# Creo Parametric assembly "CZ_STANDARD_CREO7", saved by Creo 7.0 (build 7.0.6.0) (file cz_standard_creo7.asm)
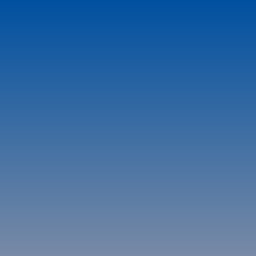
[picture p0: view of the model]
Units: Custom; MM, KILOGRAM, SECS

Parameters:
  BEARBEITER = "."
  ERSTELLUNGSDATUM = "."
  KONSTRUKTIONSGRUPPE = "."
  ZEICHNUNGSNUMMER = "000000-0000-000/01"
  TEILDOKUMENT = "001"
  VERSION = "01"
  MATERIALNUMMER = "000000-0000-000"
  KOMP_STUFE = "G"
  KOMP_CHAR = "M"
  BENENNUNG = "XXXXX"

Other parameters: PREIS

Created from: CZ_STANDARD_CREO4.ASM

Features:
  1. datum plane "A_Y-Z"
  2. datum plane "A_X-Z"
  3. datum plane "A_X-Y"
  4. coordinate system
  5. datum axis
  6. datum axis
  7. datum axis

Other named items: X0Y0Z0, A_X-ACHSE, A_Y-ACHSE, A_Z-ACHSE, BLANK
